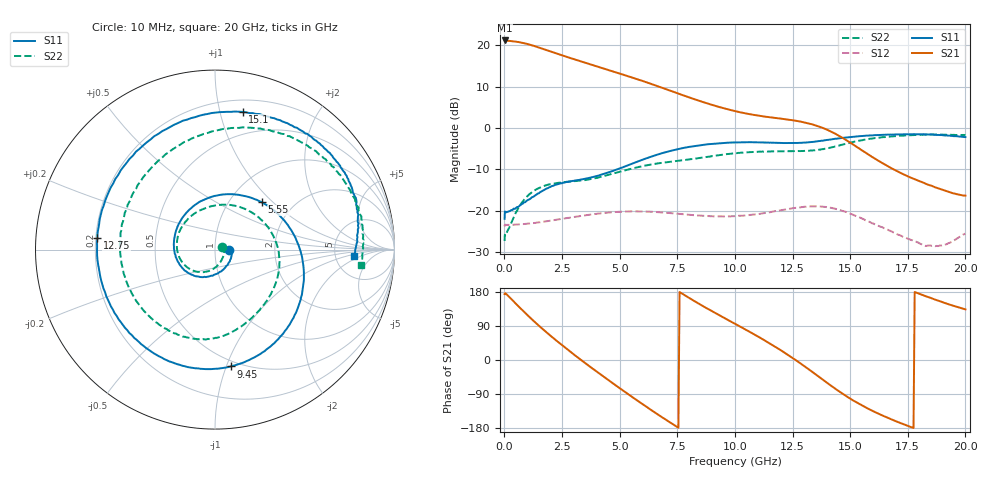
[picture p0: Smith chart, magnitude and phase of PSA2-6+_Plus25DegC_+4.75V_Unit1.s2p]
!Keysight Technologies,N5242A,MY47200155,A.10.49.08
!Date: Thursday, October 19, 2023 15:13:05
!Correction: S11(Full 2 Port(1,2))
!S21(Full 2 Port(1,2))
!S12(Full 2 Port(1,2))
!S22(Full 2 Port(1,2))
!S2P File: Measurements: S11, S21, S12, S22:
# Hz S  dB  R 50
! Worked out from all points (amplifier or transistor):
!   408 points, 10 MHz to 20 GHz, reference 50 ohm
!   highest |S21| = 21.1 dB at 10 MHz (marker M1)
!   |S21| within 3 dB of that: start of sweep to 2.183 GHz
!   unconditionally stable (mu >= 1): start of sweep to end of sweep
!   at 3.05 GHz: K = 1.02, MAG = 18.1 dB, |S12| = -21.5 dB
!   at 9.85 GHz: K = 1.37, MAG = 9.2 dB, |S12| = -21.3 dB
!   at 20 GHz: K = 7.73, MAG = -7.3 dB, |S12| = -25.5 dB
!   S11 on the Smith chart (normalised r, x): 10 MHz: 1.17, -0.00; 5.55 GHz: 1.40, +0.86; 9.45 GHz: 0.45, -1.04; 12.75 GHz: 0.21, +0.05; 15.1 GHz: 0.30, +1.18; 20 GHz: 7.65, -1.45
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1e7  -21.97 -1.2  21.14 173.9  -23.77 -3.6  -27.29 22.6
7e7  -20.36 -7.1  21.06 174.7  -23.43 -1.7  -25.42 -14.7
4e8  -19.51 -38.5  20.91 154.6  -23.40 -6.6  -21.67 -74.0
8e8  -18.28 -70.2  20.54 130.3  -23.25 -13.2  -17.76 -109.9
1.05e9  -17.35 -86.8  20.21 115.6  -23.11 -17.5  -16.19 -126.6
1.35e9  -16.24 -103.2  19.71 98.6  -22.94 -22.9  -14.95 -143.5
1.85e9  -14.60 -128.4  18.77 71.8  -22.53 -32.4  -13.78 -169.5
2.35e9  -13.55 -152.5  17.83 46.5  -22.10 -42.9  -13.26 166.1
2.85e9  -12.93 -176.6  16.91 22.3  -21.67 -54.1  -12.98 141.7
3.35e9  -12.45 158.5  16.01 -1.1  -21.24 -66.2  -12.69 117.1
3.9e9  -11.77 130.5  15.05 -26.0  -20.82 -80.2  -12.21 90.7
4.45e9  -10.87 101.1  14.10 -50.3  -20.48 -94.9  -11.41 65.5
5.55e9  -8.61 45.1  12.17 -97.9  -20.17 -125.5  -9.80 20.5
6.7e9  -6.34 -3.2  9.99 -145.4  -20.36 -157.1  -8.53 -17.9
8.1e9  -4.50 -48.0  7.22 160.7  -21.02 167.7  -7.55 -54.5
9.45e9  -3.65 -82.4  4.86 113.8  -21.37 138.4  -6.48 -80.8
1.005e10  -3.49 -96.9  4.01 93.9  -21.26 126.4  -6.10 -91.6
1.275e10  -3.63 174.2  1.63 -4.9  -19.21 57.5  -5.58 -165.4
1.335e10  -3.39 146.9  0.88 -31.2  -18.95 37.0  -5.48 167.5
1.51e10  -2.13 78.7  -3.89 -105.5  -20.90 -25.2  -3.42 86.0
1.67e10  -1.62 44.6  -9.44 -154.2  -24.78 -65.8  -2.10 43.3
2e10  -2.20 -2.8  -16.36 133.5  -25.54 -94.0  -1.73 -6.0
